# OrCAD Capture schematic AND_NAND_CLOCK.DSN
size A

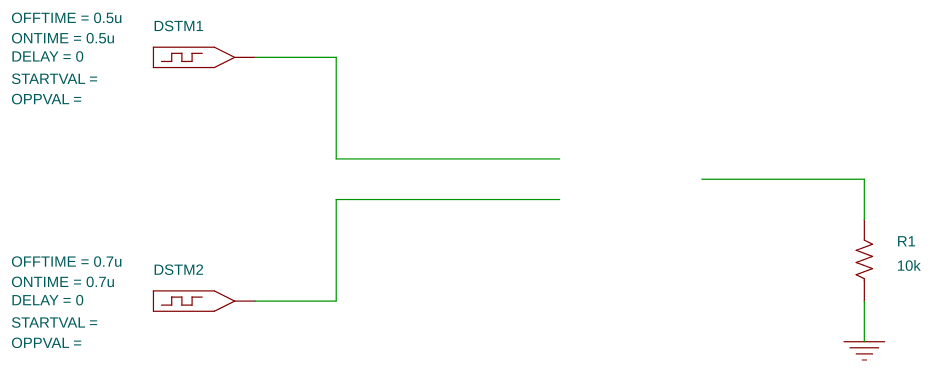
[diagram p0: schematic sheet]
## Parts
DSTM1  DigitalPulse_app
DSTM2  DigitalPulse_app
R1  10k  [AXRC05]

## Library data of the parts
DSTM1 = DigitalPulse_app: AppProp: OFFTIME=0.5u,ONTIME=0.5u,DELAY=0,ROUT=10,VOH=5,VOL=0; DELAY: 0; OFFTIME: 0.5u; ONTIME: 0.5u
DSTM2 = DigitalPulse_app: AppProp: OFFTIME=0.7u,ONTIME=0.7u,DELAY=0,ROUT=10,VOH=5,VOL=0; DELAY: 0; OFFTIME: 0.7u; ONTIME: 0.7u
R1 = R

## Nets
0: R1.1

Not connected (* = marked no-connect by the designer): DSTM1 1; DSTM2 1; R1 2
